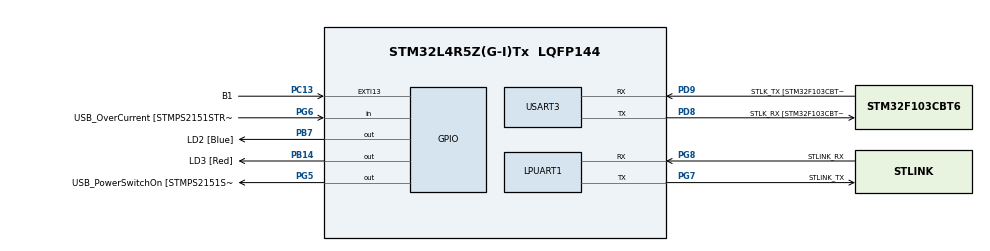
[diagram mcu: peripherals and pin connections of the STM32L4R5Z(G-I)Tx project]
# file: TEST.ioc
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Mcu.Family=STM32L4
Mcu.Name=STM32L4R5Z(G-I)Tx
Mcu.Package=LQFP144
NVIC.EXTI15_10_IRQn=true\:0\:0\:false\:false\:true\:true\:true
NVIC.PriorityGroup=NVIC_PRIORITYGROUP_4
NVIC.USART3_IRQn=true\:0\:0\:false\:false\:true\:true\:true
PA10.GPIO_Label=USB_ID
PA10.Signal=USB_OTG_FS_ID
PA11.GPIO_Label=USB_DM
PA11.Signal=USB_OTG_FS_DM
PA12.GPIO_Label=USB_DP
PA12.Signal=USB_OTG_FS_DP
PA13\ (JTMS/SWDIO).GPIO_Label=TMS
PA13\ (JTMS/SWDIO).Mode=Trace_Asynchronous_SW
PA13\ (JTMS/SWDIO).Signal=SYS_JTMS-SWDIO
PA14\ (JTCK/SWCLK).GPIO_Label=TCK
PA14\ (JTCK/SWCLK).Mode=Trace_Asynchronous_SW
PA14\ (JTCK/SWCLK).Signal=SYS_JTCK-SWCLK
PA8.GPIO_Label=USB_SOF [TP1]
PA8.Signal=USB_OTG_FS_SOF
PA9.GPIO_Label=USB_VBUS
PA9.Signal=USB_OTG_FS_VBUS
PB14.GPIO_Label=LD3 [Red]
PB14.Signal=GPIO_Output
PB3\ (JTDO/TRACESWO).GPIO_Label=SWO
PB3\ (JTDO/TRACESWO).Mode=Trace_Asynchronous_SW
PB3\ (JTDO/TRACESWO).Signal=SYS_JTDO-SWO
PB7.GPIO_Label=LD2 [Blue]
PB7.Signal=GPIO_Output
PC13.GPIO_Label=B1
PC13.Signal=GPXTI13
PC14-OSC32_IN\ (PC14).Mode=LSE-External-Oscillator
PC14-OSC32_IN\ (PC14).Signal=RCC_OSC32_IN
PC15-OSC32_OUT\ (PC15).Mode=LSE-External-Oscillator
PC15-OSC32_OUT\ (PC15).Signal=RCC_OSC32_OUT
PD8.GPIO_Label=STLK_RX [STM32F103CBT6_PA3]
PD8.Mode=Asynchronous
PD8.Signal=USART3_TX
PD9.GPIO_Label=STLK_TX [STM32F103CBT6_PA2]
PD9.Mode=Asynchronous
PD9.Signal=USART3_RX
PG5.GPIO_Label=USB_PowerSwitchOn [STMPS2151STR_EN]
PG5.Signal=GPIO_Output
PG6.GPIO_Label=USB_OverCurrent [STMPS2151STR_FAULT]
PG6.Signal=GPIO_Input
PG7.GPIO_Label=STLINK_TX
PG7.Mode=Asynchronous
PG7.Signal=LPUART1_TX
PG8.GPIO_Label=STLINK_RX
PG8.Mode=Asynchronous
PG8.Signal=LPUART1_RX
PH0-OSC_IN\ (PH0).Mode=HSE-External-Clock-Source
PH0-OSC_IN\ (PH0).Signal=RCC_OSC_IN
PH1-OSC_OUT\ (PH1).Signal=RCC_OSC_OUT
ProjectManager.HeapSize=0x200
ProjectManager.StackSize=0x400
ProjectManager.TargetToolchain=SW4STM32
RCC.48MHZClocksFreq_Value=24000000
RCC.ADCFreq_Value=96000000
RCC.AHBCLKDivider=RCC_SYSCLK_DIV2
RCC.AHBFreq_Value=4000000
RCC.APB1CLKDivider=RCC_HCLK_DIV2
RCC.APB1Freq_Value=2000000
RCC.APB1TimFreq_Value=4000000
RCC.APB2CLKDivider=RCC_HCLK_DIV2
RCC.APB2Freq_Value=2000000
RCC.APB2TimFreq_Value=4000000
RCC.CortexFreq_Value=4000000
RCC.HCLKFreq_Value=4000000
RCC.HSE_VALUE=8000000
RCC.HSI48_VALUE=48000000
RCC.HSI_VALUE=16000000
RCC.MSI_VALUE=4000000
RCC.PLLMUL=RCC_PLL_MUL9
RCC.PLLN=60
RCC.PLLSAI1N=24
RCC.PLLSourceVirtual=RCC_PLLSOURCE_HSE
RCC.PRESCALERUSB=RCC_USBCLKSOURCE_PLL_DIV1_5
RCC.SYSCLKFreq_VALUE=8000000
RCC.SYSCLKSource=RCC_SYSCLKSOURCE_HSE
RCC.SYSCLKSourceVirtual=RCC_SYSCLKSOURCE_PLLCLK
RCC.USBFreq_Value=96000000
RCC.VCOOutputFreq_Value=480000000
USART3.VirtualMode-Asynchronous=VM_ASYNC
board=NUCLEO-L4R5ZI

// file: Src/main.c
#include "main.h"
#include <stdio.h>
#include <string.h>

UART_HandleTypeDef hlpuart1;
UART_HandleTypeDef huart1;
UART_HandleTypeDef huart3;

void SystemClock_Config(void);
static void MX_GPIO_Init(void);
static void MX_LPUART1_UART_Init(void);
static void MX_USART3_UART_Init(void);

int main(void)
{
  /* USER CODE BEGIN 1 */
	uint8_t msg[100];

  /* Reset of all peripherals, Initializes the Flash interface and the Systick. */
  HAL_Init();
  SystemClock_Config();

  /* Initialize all configured peripherals */
  MX_GPIO_Init();
  MX_LPUART1_UART_Init();
  MX_USART3_UART_Init();
  /* USER CODE BEGIN 2 */

  /*This is the only user code I had added*/
	memset(msg,0,sizeof(msg));
	sprintf(msg,"SYSCLK: %lu \r\n",HAL_RCC_GetSysClockFreq());
	//SPRINTF print the message line to string "msg", before useit to be transmitted
	HAL_UART_Transmit(&huart3, msg, strlen(msg), HAL_MAX_DELAY);

	memset(msg,0,sizeof(msg));
	sprintf(msg,"HCLK: %lu \r\n",HAL_RCC_GetHCLKFreq());
	HAL_UART_Transmit(&huart3, msg, strlen(msg), HAL_MAX_DELAY);

	memset(msg,0,sizeof(msg));
	sprintf(msg,"PCLK1: %lu \r\n",HAL_RCC_GetPCLK1Freq());
	HAL_UART_Transmit(&huart3, msg, strlen(msg), HAL_MAX_DELAY);

	memset(msg,0,sizeof(msg));
	sprintf(msg,"PCLK2: %lu \r\n",HAL_RCC_GetPCLK2Freq());
	HAL_UART_Transmit(&huart3, msg, strlen(msg), HAL_MAX_DELAY);

  /* USER CODE END 2 */

  /* Infinite loop */
  while (1)
  {
	HAL_Delay(500);
	HAL_UART_Transmit(&huart3, msg, strlen(msg), HAL_MAX_DELAY);

  }
}

void SystemClock_Config(void)
{
  RCC_OscInitTypeDef RCC_OscInitStruct = {0};
  RCC_ClkInitTypeDef RCC_ClkInitStruct = {0};
  RCC_PeriphCLKInitTypeDef PeriphClkInit = {0};

  /** Configure the main internal regulator output voltage
  */
  if (HAL_PWREx_ControlVoltageScaling(PWR_REGULATOR_VOLTAGE_SCALE1) != HAL_OK)
  {
    Error_Handler();
  }
  /** Initializes the CPU, AHB and APB busses clocks
  */
  RCC_OscInitStruct.OscillatorType = RCC_OSCILLATORTYPE_HSI;
  RCC_OscInitStruct.HSIState = RCC_HSI_ON;
  RCC_OscInitStruct.HSICalibrationValue = RCC_HSICALIBRATION_DEFAULT;
  RCC_OscInitStruct.PLL.PLLState = RCC_PLL_NONE;
  if (HAL_RCC_OscConfig(&RCC_OscInitStruct) != HAL_OK)
  {
    Error_Handler();
  }
  /** Initializes the CPU, AHB and APB busses clocks
  */
  RCC_ClkInitStruct.ClockType = RCC_CLOCKTYPE_HCLK|RCC_CLOCKTYPE_SYSCLK
                              |RCC_CLOCKTYPE_PCLK1|RCC_CLOCKTYPE_PCLK2;
  RCC_ClkInitStruct.SYSCLKSource = RCC_SYSCLKSOURCE_HSI;
  RCC_ClkInitStruct.AHBCLKDivider = RCC_SYSCLK_DIV4;
  RCC_ClkInitStruct.APB1CLKDivider = RCC_HCLK_DIV2;
  RCC_ClkInitStruct.APB2CLKDivider = RCC_HCLK_DIV2;

  if (HAL_RCC_ClockConfig(&RCC_ClkInitStruct, FLASH_LATENCY_0) != HAL_OK)
  {
    Error_Handler();
  }
  PeriphClkInit.PeriphClockSelection = RCC_PERIPHCLK_USART3|RCC_PERIPHCLK_LPUART1;
  PeriphClkInit.Usart3ClockSelection = RCC_USART3CLKSOURCE_PCLK1;
  PeriphClkInit.Lpuart1ClockSelection = RCC_LPUART1CLKSOURCE_PCLK1;
  if (HAL_RCCEx_PeriphCLKConfig(&PeriphClkInit) != HAL_OK)
  {
    Error_Handler();
  }
}

static void MX_LPUART1_UART_Init(void)
{

  hlpuart1.Instance = LPUART1;
  hlpuart1.Init.BaudRate = 209700;
  hlpuart1.Init.WordLength = UART_WORDLENGTH_7B;
  hlpuart1.Init.StopBits = UART_STOPBITS_1;
  hlpuart1.Init.Parity = UART_PARITY_NONE;
  hlpuart1.Init.Mode = UART_MODE_TX_RX;
  hlpuart1.Init.HwFlowCtl = UART_HWCONTROL_NONE;
  hlpuart1.Init.OneBitSampling = UART_ONE_BIT_SAMPLE_DISABLE;
  hlpuart1.Init.ClockPrescaler = UART_PRESCALER_DIV1;
  hlpuart1.AdvancedInit.AdvFeatureInit = UART_ADVFEATURE_NO_INIT;
  hlpuart1.FifoMode = UART_FIFOMODE_DISABLE;
  if (HAL_UART_Init(&hlpuart1) != HAL_OK)
  {
    Error_Handler();
  }
  if (HAL_UARTEx_SetTxFifoThreshold(&hlpuart1, UART_TXFIFO_THRESHOLD_1_8) != HAL_OK)
  {
    Error_Handler();
  }
  if (HAL_UARTEx_SetRxFifoThreshold(&hlpuart1, UART_RXFIFO_THRESHOLD_1_8) != HAL_OK)
  {
    Error_Handler();
  }
  if (HAL_UARTEx_DisableFifoMode(&huart1) != HAL_OK)
  {
    Error_Handler();
  }

}

static void MX_USART3_UART_Init(void)
{

  huart3.Instance = USART3;
  huart3.Init.BaudRate = 115200;
  huart3.Init.WordLength = UART_WORDLENGTH_8B;
  huart3.Init.StopBits = UART_STOPBITS_1;
  huart3.Init.Parity = UART_PARITY_NONE;
  huart3.Init.Mode = UART_MODE_TX_RX;
  huart3.Init.HwFlowCtl = UART_HWCONTROL_NONE;
  huart3.Init.OverSampling = UART_OVERSAMPLING_16;
  huart3.Init.OneBitSampling = UART_ONE_BIT_SAMPLE_DISABLE;
  huart3.Init.ClockPrescaler = UART_PRESCALER_DIV1;
  huart3.AdvancedInit.AdvFeatureInit = UART_ADVFEATURE_NO_INIT;
  if (HAL_UART_Init(&huart3) != HAL_OK)
  {
    Error_Handler();
  }
  if (HAL_UARTEx_SetTxFifoThreshold(&huart3, UART_TXFIFO_THRESHOLD_1_8) != HAL_OK)
  {
    Error_Handler();
  }
  if (HAL_UARTEx_SetRxFifoThreshold(&huart3, UART_RXFIFO_THRESHOLD_1_8) != HAL_OK)
  {
    Error_Handler();
  }
  if (HAL_UARTEx_DisableFifoMode(&huart3) != HAL_OK)
  {
    Error_Handler();
  }

}

static void MX_GPIO_Init(void)
{
  GPIO_InitTypeDef GPIO_InitStruct = {0};

  /* GPIO Ports Clock Enable */
  __HAL_RCC_GPIOC_CLK_ENABLE();
  __HAL_RCC_GPIOH_CLK_ENABLE();
  __HAL_RCC_GPIOB_CLK_ENABLE();
  __HAL_RCC_GPIOD_CLK_ENABLE();
  __HAL_RCC_GPIOG_CLK_ENABLE();
  HAL_PWREx_EnableVddIO2();
  __HAL_RCC_GPIOA_CLK_ENABLE();

  /*Configure GPIO pin Output Level */
  HAL_GPIO_WritePin(GPIOB, LD3_Pin|LD2_Pin, GPIO_PIN_RESET);

  /*Configure GPIO pin Output Level */
  HAL_GPIO_WritePin(USB_PowerSwitchOn_GPIO_Port, USB_PowerSwitchOn_Pin, GPIO_PIN_RESET);

  /*Configure GPIO pin : B1_Pin */
  GPIO_InitStruct.Pin = B1_Pin;
  GPIO_InitStruct.Mode = GPIO_MODE_IT_RISING;
  GPIO_InitStruct.Pull = GPIO_NOPULL;
  HAL_GPIO_Init(B1_GPIO_Port, &GPIO_InitStruct);

  /*Configure GPIO pins : LD3_Pin LD2_Pin */
  GPIO_InitStruct.Pin = LD3_Pin|LD2_Pin;
  GPIO_InitStruct.Mode = GPIO_MODE_OUTPUT_PP;
  GPIO_InitStruct.Pull = GPIO_NOPULL;
  GPIO_InitStruct.Speed = GPIO_SPEED_FREQ_LOW;
  HAL_GPIO_Init(GPIOB, &GPIO_InitStruct);

  /*Configure GPIO pin : USB_PowerSwitchOn_Pin */
  GPIO_InitStruct.Pin = USB_PowerSwitchOn_Pin;
  GPIO_InitStruct.Mode = GPIO_MODE_OUTPUT_PP;
  GPIO_InitStruct.Pull = GPIO_NOPULL;
  GPIO_InitStruct.Speed = GPIO_SPEED_FREQ_LOW;
  HAL_GPIO_Init(USB_PowerSwitchOn_GPIO_Port, &GPIO_InitStruct);

  /*Configure GPIO pin : USB_OverCurrent_Pin */
  GPIO_InitStruct.Pin = USB_OverCurrent_Pin;
  GPIO_InitStruct.Mode = GPIO_MODE_INPUT;
  GPIO_InitStruct.Pull = GPIO_NOPULL;
  HAL_GPIO_Init(USB_OverCurrent_GPIO_Port, &GPIO_InitStruct);

  /*Configure GPIO pins : USB_SOF_Pin USB_ID_Pin USB_DM_Pin USB_DP_Pin */
  GPIO_InitStruct.Pin = USB_SOF_Pin|USB_ID_Pin|USB_DM_Pin|USB_DP_Pin;
  GPIO_InitStruct.Mode = GPIO_MODE_AF_PP;
  GPIO_InitStruct.Pull = GPIO_NOPULL;
  GPIO_InitStruct.Speed = GPIO_SPEED_FREQ_VERY_HIGH;
  GPIO_InitStruct.Alternate = GPIO_AF10_OTG_FS;
  HAL_GPIO_Init(GPIOA, &GPIO_InitStruct);

  /*Configure GPIO pin : USB_VBUS_Pin */
  GPIO_InitStruct.Pin = USB_VBUS_Pin;
  GPIO_InitStruct.Mode = GPIO_MODE_INPUT;
  GPIO_InitStruct.Pull = GPIO_NOPULL;
  HAL_GPIO_Init(USB_VBUS_GPIO_Port, &GPIO_InitStruct);

  /* EXTI interrupt init*/
  HAL_NVIC_SetPriority(EXTI15_10_IRQn, 0, 0);
  HAL_NVIC_EnableIRQ(EXTI15_10_IRQn);

}

void Error_Handler(void)
{
}
